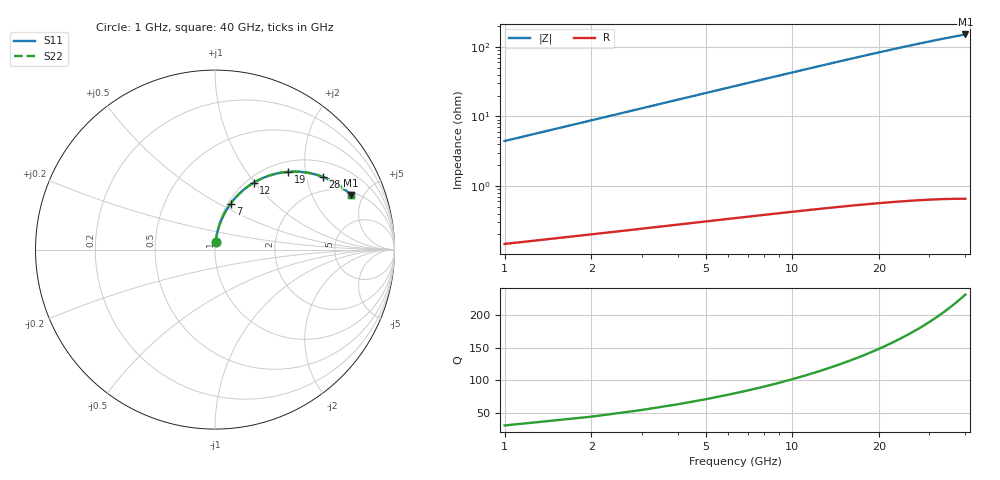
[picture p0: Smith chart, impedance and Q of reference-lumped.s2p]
# GHz S RI R 50
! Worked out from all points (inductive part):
!   40 points, 1 GHz to 40 GHz, reference 50 ohm
!   read as one part in series: L = 698 pH near 1 GHz
!   highest Q = 232 at 40 GHz (marker M1), where L = 602 pH
!   S11 on the Smith chart (normalised r, x): 1 GHz: 1.00, +0.08; 7 GHz: 1.03, +0.57; 12 GHz: 1.08, +0.99; 19 GHz: 1.20, +1.61; 28 GHz: 1.47, +2.51; 40 GHz: 2.21, +4.01
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1  0.00339 0.0411  0.9966 -0.0469  0.9966 -0.0469  0.00339 0.0411
2  0.00956 0.0809  0.9904 -0.0925  0.9904 -0.0925  0.00956 0.0809
3  0.0191 0.1196  0.9807 -0.137  0.9807 -0.137  0.0191 0.1196
4  0.0319 0.1569  0.9678 -0.18  0.9678 -0.18  0.0319 0.1569
5  0.0478 0.1923  0.9518 -0.2212  0.9518 -0.2212  0.0478 0.1923
6  0.0663 0.2256  0.9331 -0.2603  0.9331 -0.2603  0.0663 0.2256
7  0.0872 0.2567  0.9119 -0.2971  0.9119 -0.2971  0.0872 0.2567
8  0.1102 0.2852  0.8887 -0.3314  0.8887 -0.3314  0.1102 0.2852
9  0.1349 0.3111  0.8638 -0.3631  0.8638 -0.3631  0.1349 0.3111
10  0.1608 0.3343  0.8375 -0.3921  0.8375 -0.3921  0.1608 0.3343
12  0.2154 0.3728  0.7822 -0.442  0.7822 -0.442  0.2154 0.3728
14  0.2716 0.401  0.7252 -0.4818  0.7252 -0.4818  0.2716 0.401
16  0.3273 0.42  0.6684 -0.5122  0.6684 -0.5122  0.3273 0.42
19  0.4071 0.4335  0.5869 -0.5429  0.5869 -0.5429  0.4071 0.4335
21  0.4565 0.4345  0.5361 -0.5554  0.5361 -0.5554  0.4565 0.4345
24  0.524 0.4269  0.4665 -0.5649  0.4665 -0.5649  0.524 0.4269
27  0.583 0.4114  0.4049 -0.5664  0.4049 -0.5664  0.583 0.4114
28  0.6009 0.405  0.3861 -0.5657  0.3861 -0.5657  0.6009 0.405
31  0.6495 0.3829  0.3346 -0.5605  0.3346 -0.5605  0.6495 0.3829
34  0.6911 0.3579  0.2898 -0.5525  0.2898 -0.5525  0.6911 0.3579
37  0.7265 0.3315  0.2509 -0.5428  0.2509 -0.5428  0.7265 0.3315
40  0.7567 0.3043  0.217 -0.5323  0.217 -0.5323  0.7567 0.3043
